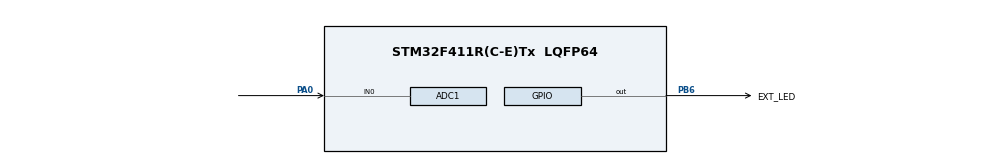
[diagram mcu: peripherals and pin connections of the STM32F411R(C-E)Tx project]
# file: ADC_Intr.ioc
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ADC1.Channel-0\#ChannelRegularConversion=ADC_CHANNEL_0
ADC1.ContinuousConvMode=ENABLE
ADC1.NbrOfConversionFlag=1
ADC1.Rank-0\#ChannelRegularConversion=1
ADC1.SamplingTime-0\#ChannelRegularConversion=ADC_SAMPLETIME_480CYCLES
ADC1.master=1
Mcu.Family=STM32F4
Mcu.Name=STM32F411R(C-E)Tx
Mcu.Package=LQFP64
NVIC.ADC_IRQn=true\:0\:0\:false\:false\:true\:true\:true\:true
NVIC.PriorityGroup=NVIC_PRIORITYGROUP_4
PA0-WKUP.Signal=ADCx_IN0
PB6.GPIO_Label=EXT_LED
PB6.Signal=GPIO_Output
ProjectManager.HeapSize=0x200
ProjectManager.StackSize=0x400
ProjectManager.TargetToolchain=STM32CubeIDE
RCC.AHBFreq_Value=16000000
RCC.APB1Freq_Value=16000000
RCC.APB2Freq_Value=16000000
RCC.CortexFreq_Value=16000000
RCC.HSE_VALUE=25000000
RCC.HSI_VALUE=16000000
RCC.LSE_VALUE=32768
RCC.SYSCLKFreq_VALUE=16000000
RCC.VCOOutputFreq_Value=192000000
SH.ADCx_IN0.0=ADC1_IN0,IN0
board=custom

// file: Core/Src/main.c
/* USER CODE BEGIN Header */
/**
  ******************************************************************************
  * @file           : main.c
  * @brief          : Main program body
  ******************************************************************************
  * @attention
  *
  * Copyright (c) 2022 STMicroelectronics.
  * All rights reserved.
  *
  * This software is licensed under terms that can be found in the LICENSE file
  * in the root directory of this software component.
  * If no LICENSE file comes with this software, it is provided AS-IS.
  *
  ******************************************************************************
  */
/* USER CODE END Header */
#include "main.h"
#include "lcd.h"

ADC_HandleTypeDef hadc1;

/* USER CODE BEGIN PV */
uint16_t adc_value;
/* USER CODE END PV */

void SystemClock_Config(void);
static void MX_GPIO_Init(void);
static void MX_ADC1_Init(void);

int main(void)
{
  /* USER CODE BEGIN 1 */
char str[] = { "ADC_INTERFACE" };
char str1[] = { "ADC :" };
  /* USER CODE END 1 */

  /* MCU Configuration--------------------------------------------------------*/

  /* Reset of all peripherals, Initializes the Flash interface and the Systick. */
  HAL_Init();
  LCD_init();

  /* Configure the system clock */
  SystemClock_Config();

  /* USER CODE BEGIN SysInit */
//  HAL_ADC_Start_IT(&hadc1);
  /* USER CODE END SysInit */

  /* Initialize all configured peripherals */
  MX_GPIO_Init();
  MX_ADC1_Init();
  LCD_command(0x82);
  LCD_string(str);
  LCD_command(0xC4);
  LCD_string(str1);

  /* Infinite loop */
  while (1)
  {
 HAL_ADC_Start(&hadc1);
 if(HAL_ADC_PollForConversion(&hadc1, 10) == 0)
 {
   adc_value = HAL_ADC_GetValue(&hadc1);
   LCD_command(0xC9);
   LCD_data((adc_value/1000) + 48);
   LCD_data(((adc_value / 100) % 10) + 48);
   LCD_data(((adc_value / 10) % 10) + 48);
   LCD_data((adc_value % 10) + 48);
 }
 if(adc_value > 3900)
 {
   HAL_GPIO_WritePin(GPIOB, GPIO_PIN_6, 1);
 }
 else
 {
   HAL_GPIO_WritePin(GPIOB, GPIO_PIN_6, 0);
 }
  }
}
//void HAL_ADC_ConvCpltCallback(ADC_HandleTypeDef* hadc)
//{
//	uint16_t adc_value= HAL_ADC_GetValue(&hadc1);
//	 if(HAL_ADC_PollForConversion(&hadc1, 10) == 0)
//	 {
//	   adc_value = HAL_ADC_GetValue(&hadc1);
//	   LCD_command(0xC9);
//	   LCD_data((adc_value/1000) + 48);
//	   LCD_data(((adc_value / 100) % 10) + 48);
//	   LCD_data(((adc_value / 10) % 10) + 48);
//	   LCD_data((adc_value % 10) + 48);
//	   delay(100);
//	 }
//	 if(adc_value > 2040)
//	 {
//	   HAL_GPIO_WritePin(GPIOB, GPIO_PIN_6, 1);
//	 }
//	 else
//	 {
//	   HAL_GPIO_WritePin(GPIOB, GPIO_PIN_6, 0);
//	 }
//	 delay(100);
//}
void SystemClock_Config(void)
{
  RCC_OscInitTypeDef RCC_OscInitStruct = {0};
  RCC_ClkInitTypeDef RCC_ClkInitStruct = {0};

  /** Configure the main internal regulator output voltage
  */
  __HAL_RCC_PWR_CLK_ENABLE();
  __HAL_PWR_VOLTAGESCALING_CONFIG(PWR_REGULATOR_VOLTAGE_SCALE1);

  /** Initializes the RCC Oscillators according to the specified parameters
  * in the RCC_OscInitTypeDef structure.
  */
  RCC_OscInitStruct.OscillatorType = RCC_OSCILLATORTYPE_HSI;
  RCC_OscInitStruct.HSIState = RCC_HSI_ON;
  RCC_OscInitStruct.HSICalibrationValue = RCC_HSICALIBRATION_DEFAULT;
  RCC_OscInitStruct.PLL.PLLState = RCC_PLL_NONE;
  if (HAL_RCC_OscConfig(&RCC_OscInitStruct) != HAL_OK)
  {
    Error_Handler();
  }

  /** Initializes the CPU, AHB and APB buses clocks
  */
  RCC_ClkInitStruct.ClockType = RCC_CLOCKTYPE_HCLK|RCC_CLOCKTYPE_SYSCLK
                              |RCC_CLOCKTYPE_PCLK1|RCC_CLOCKTYPE_PCLK2;
  RCC_ClkInitStruct.SYSCLKSource = RCC_SYSCLKSOURCE_HSI;
  RCC_ClkInitStruct.AHBCLKDivider = RCC_SYSCLK_DIV1;
  RCC_ClkInitStruct.APB1CLKDivider = RCC_HCLK_DIV2;
  RCC_ClkInitStruct.APB2CLKDivider = RCC_HCLK_DIV1;

  if (HAL_RCC_ClockConfig(&RCC_ClkInitStruct, FLASH_LATENCY_0) != HAL_OK)
  {
    Error_Handler();
  }
}

static void MX_ADC1_Init(void)
{

  ADC_ChannelConfTypeDef sConfig = {0};

  /** Configure the global features of the ADC (Clock, Resolution, Data Alignment and number of conversion)
  */
  hadc1.Instance = ADC1;
  hadc1.Init.ClockPrescaler = ADC_CLOCK_SYNC_PCLK_DIV2;
  hadc1.Init.Resolution = ADC_RESOLUTION_12B;
  hadc1.Init.ScanConvMode = DISABLE;
  hadc1.Init.ContinuousConvMode = ENABLE;
  hadc1.Init.DiscontinuousConvMode = DISABLE;
  hadc1.Init.ExternalTrigConvEdge = ADC_EXTERNALTRIGCONVEDGE_NONE;
  hadc1.Init.ExternalTrigConv = ADC_SOFTWARE_START;
  hadc1.Init.DataAlign = ADC_DATAALIGN_RIGHT;
  hadc1.Init.NbrOfConversion = 1;
  hadc1.Init.DMAContinuousRequests = DISABLE;
  hadc1.Init.EOCSelection = ADC_EOC_SINGLE_CONV;
  if (HAL_ADC_Init(&hadc1) != HAL_OK)
  {
    Error_Handler();
  }

  /** Configure for the selected ADC regular channel its corresponding rank in the sequencer and its sample time.
  */
  sConfig.Channel = ADC_CHANNEL_0;
  sConfig.Rank = 1;
  sConfig.SamplingTime = ADC_SAMPLETIME_480CYCLES;
  if (HAL_ADC_ConfigChannel(&hadc1, &sConfig) != HAL_OK)
  {
    Error_Handler();
  }

}

static void MX_GPIO_Init(void)
{
  GPIO_InitTypeDef GPIO_InitStruct = {0};

  /* GPIO Ports Clock Enable */
  __HAL_RCC_GPIOC_CLK_ENABLE();
  __HAL_RCC_GPIOH_CLK_ENABLE();
  __HAL_RCC_GPIOA_CLK_ENABLE();
  __HAL_RCC_GPIOB_CLK_ENABLE();

  /*Configure GPIO pin Output Level */
  HAL_GPIO_WritePin(EXT_LED_GPIO_Port, EXT_LED_Pin, GPIO_PIN_RESET);

  /*Configure GPIO pin : EXT_LED_Pin */
  GPIO_InitStruct.Pin = EXT_LED_Pin;
  GPIO_InitStruct.Mode = GPIO_MODE_OUTPUT_PP;
  GPIO_InitStruct.Pull = GPIO_NOPULL;
  GPIO_InitStruct.Speed = GPIO_SPEED_FREQ_LOW;
  HAL_GPIO_Init(EXT_LED_GPIO_Port, &GPIO_InitStruct);

}

void Error_Handler(void)
{
  __disable_irq();
  while (1)
  {
  }
}
